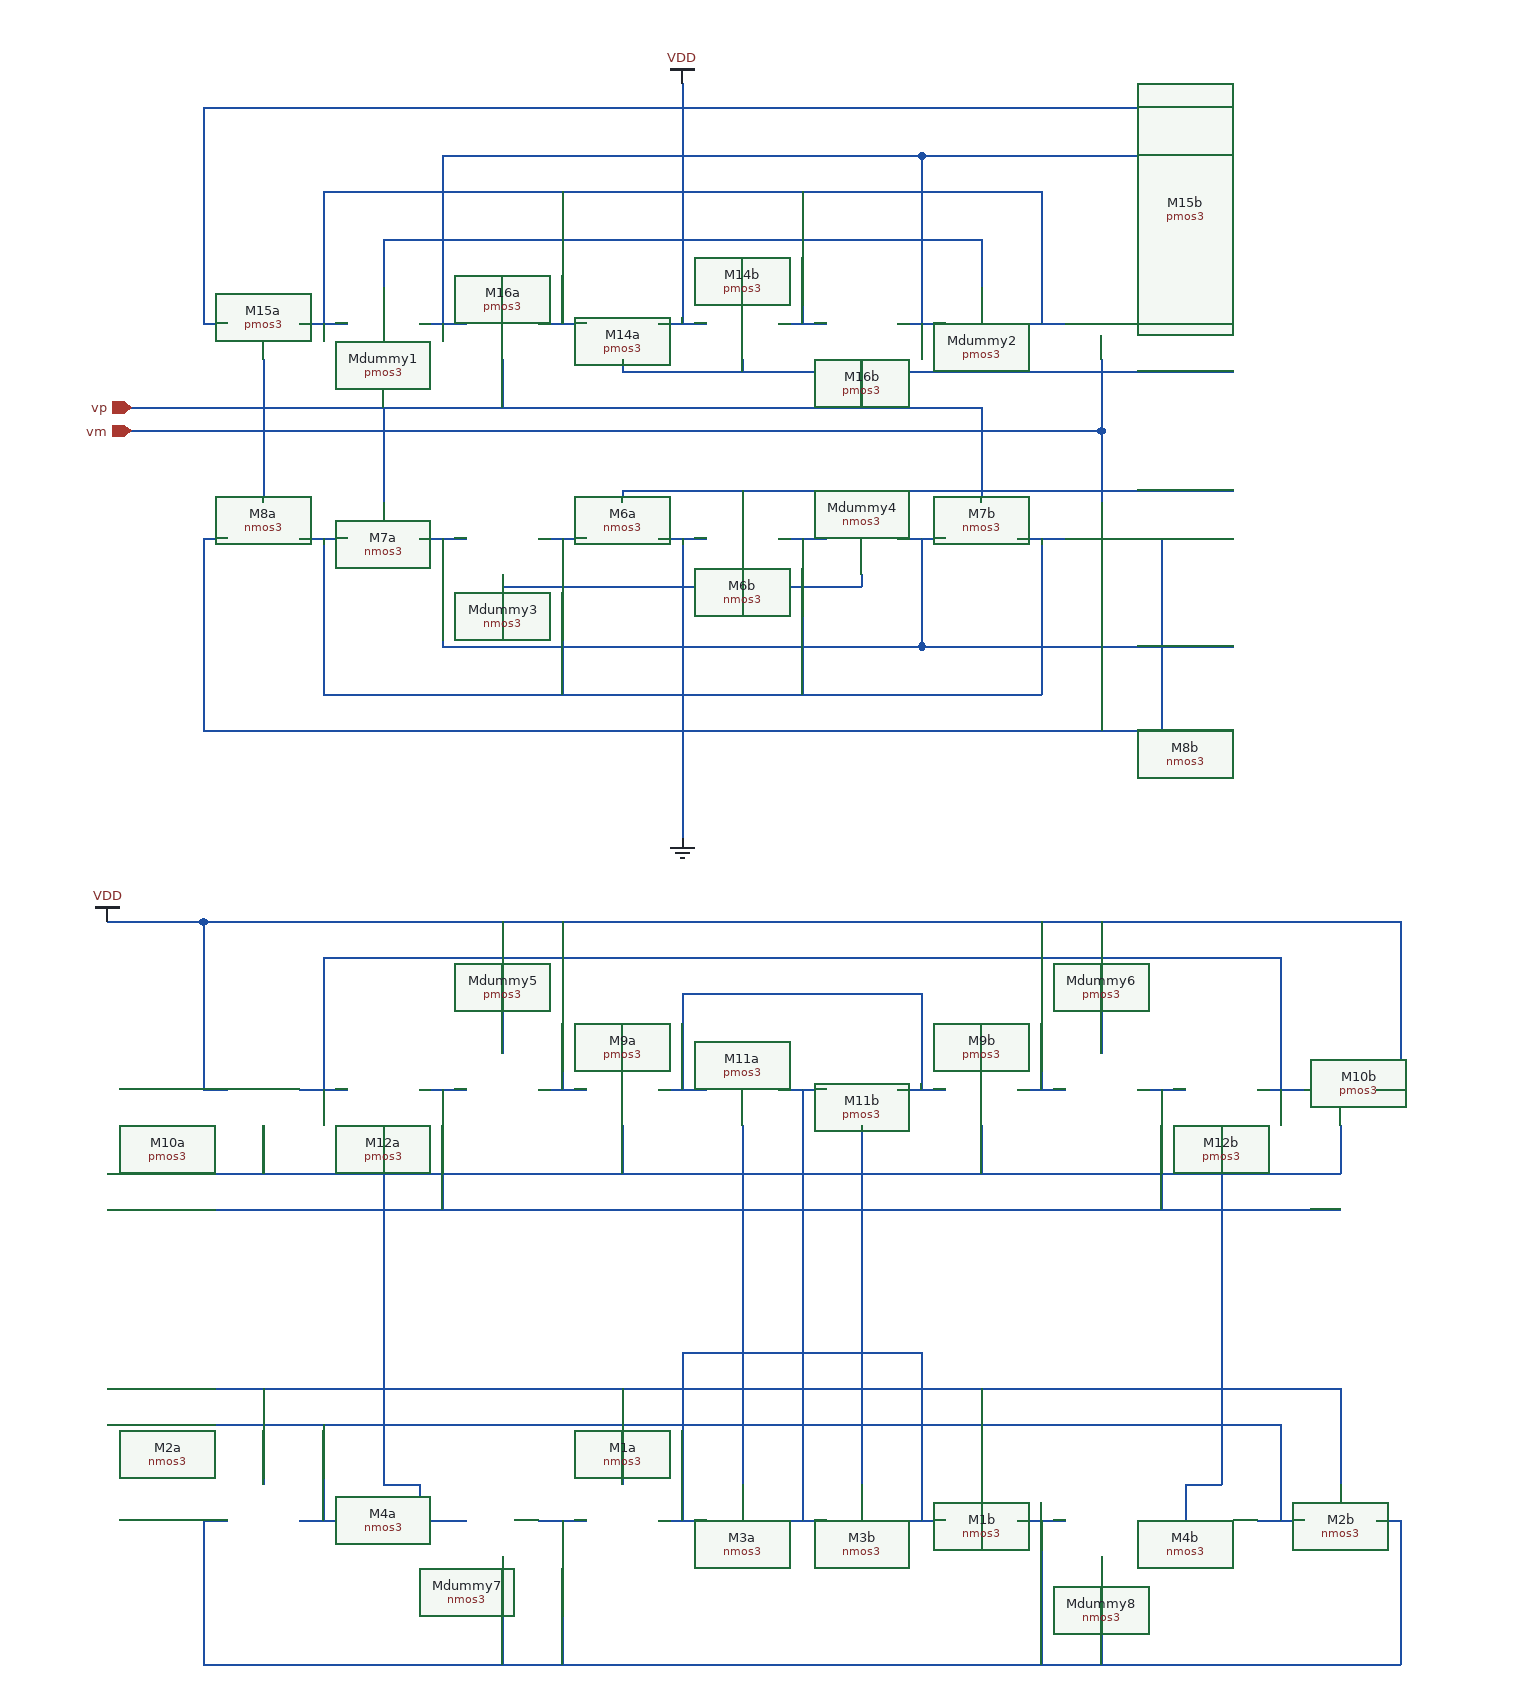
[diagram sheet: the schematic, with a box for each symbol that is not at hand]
v {xschem version=2.9.9 file_version=1.2 }
G {}
K {}
V {}
S {}
E {}
N 1240 -140 1280 -140 { lab=VDD}
N 1260 -340 1260 -140 { lab=VDD}
N 1240 40 1280 40 { lab=GND}
N 1260 40 1260 290 { lab=GND}
N 1140 40 1180 40 { lab=#net1}
N 1340 40 1380 40 { lab=#net1}
N 1210 -0 1210 10 { lab=#net2}
N 1310 -0 1310 10 { lab=#net2}
N 1210 -0 1720 -0 { lab=#net2}
N 1040 40 1080 40 { lab=#net3}
N 1440 40 1480 40 { lab=#net3}
N 940 40 980 40 { lab=#net1}
N 1540 40 1580 40 { lab=#net1}
N 1140 -140 1180 -140 { lab=#net4}
N 1340 -140 1380 -140 { lab=#net4}
N 1040 -140 1080 -140 { lab=#net5}
N 1440 -140 1480 -140 { lab=#net5}
N 940 -140 980 -140 { lab=#net4}
N 1540 -140 1580 -140 { lab=#net4}
N 1210 -110 1210 -100 { lab=#net6}
N 1210 -100 1720 -100 { lab=#net6}
N 1310 -110 1310 -100 { lab=#net6}
N 1110 80 1260 80 { lab=GND}
N 1260 80 1410 80 { lab=GND}
N 860 40 860 200 { lab=#net7}
N 1660 40 1660 200 { lab=#net7}
N 860 200 1720 200 { lab=#net7}
N 1640 40 1660 40 { lab=#net7}
N 860 40 880 40 { lab=#net7}
N 960 40 960 170 { lab=#net1}
N 960 170 1560 170 { lab=#net1}
N 1560 40 1560 170 { lab=#net1}
N 1160 40 1160 170 { lab=#net1}
N 1360 40 1360 170 { lab=#net1}
N 1110 70 1110 80 { lab=GND}
N 1410 70 1410 80 { lab=GND}
N 1060 40 1060 130 { lab=#net3}
N 1060 130 1460 130 { lab=#net3}
N 1460 40 1460 130 { lab=#net3}
N 1460 130 1720 130 { lab=#net3}
N 1010 -210 1260 -210 { lab=VDD}
N 1260 -210 1510 -210 { lab=VDD}
N 1510 -210 1510 -170 { lab=VDD}
N 1010 -210 1010 -170 { lab=VDD}
N 860 -140 880 -140 { lab=#net8}
N 1640 -140 1660 -140 { lab=#net8}
N 960 -250 960 -140 { lab=#net4}
N 960 -250 1560 -250 { lab=#net4}
N 1560 -250 1560 -140 { lab=#net4}
N 1160 -250 1160 -140 { lab=#net4}
N 1360 -250 1360 -140 { lab=#net4}
N 1060 -280 1060 -140 { lab=#net5}
N 1060 -280 1460 -280 { lab=#net5}
N 1460 -280 1460 -140 { lab=#net5}
N 1460 -280 1720 -280 { lab=#net5}
N 860 -320 860 -140 { lab=#net8}
N 860 -320 1660 -320 { lab=#net8}
N 1660 -320 1660 -140 { lab=#net8}
N 1660 -320 1720 -320 { lab=#net8}
N 800 -50 1610 -50 { lab=vm}
N 1610 -50 1610 10 { lab=vm}
N 1610 -110 1610 -50 { lab=vm}
N 910 -110 910 -50 { lab=vm}
N 910 -50 910 10 { lab=vm}
N 800 -70 1510 -70 { lab=vp}
N 1510 -70 1510 10 { lab=vp}
N 1410 -110 1410 -70 { lab=vp}
N 1010 -70 1010 10 { lab=vp}
N 1110 -110 1110 -70 { lab=vp}
N 860 500 880 500 { lab=VDD}
N 860 360 860 500 { lab=VDD}
N 1840 500 1860 500 { lab=VDD}
N 1860 360 1860 500 { lab=VDD}
N 1110 360 1110 470 { lab=VDD}
N 940 500 980 500 { lab=#net9}
N 1040 500 1080 500 { lab=#net10}
N 1140 500 1180 500 { lab=VDD}
N 860 360 1860 360 { lab=VDD}
N 1610 360 1610 470 { lab=VDD}
N 1740 500 1780 500 { lab=#net9}
N 1640 500 1680 500 { lab=#net10}
N 1540 500 1580 500 { lab=VDD}
N 1440 500 1480 500 { lab=#net11}
N 1340 500 1380 500 { lab=#net12}
N 1240 500 1280 500 { lab=#net11}
N 1160 360 1160 500 { lab=VDD}
N 1560 360 1560 500 { lab=VDD}
N 780 600 1810 600 { lab=#net10}
N 1010 530 1010 600 { lab=#net10}
N 1710 530 1710 600 { lab=#net10}
N 1310 530 1310 600 { lab=#net10}
N 1410 530 1410 600 { lab=#net10}
N 1360 500 1360 700 { lab=#net12}
N 910 530 910 570 { lab=#net13}
N 1810 530 1810 570 { lab=#net13}
N 780 570 1810 570 { lab=#net13}
N 1210 530 1210 570 { lab=#net13}
N 1510 530 1510 570 { lab=#net13}
N 1260 420 1260 500 { lab=#net11}
N 1260 420 1460 420 { lab=#net11}
N 1460 420 1460 500 { lab=#net11}
N 960 390 960 500 { lab=#net9}
N 960 390 1760 390 { lab=#net9}
N 1760 390 1760 500 { lab=#net9}
N 1060 500 1060 600 { lab=#net10}
N 1660 500 1660 600 { lab=#net10}
N 780 360 860 360 { lab=VDD}
N 940 860 980 860 { lab=#net14}
N 1040 860 1080 860 { lab=#net10}
N 1140 860 1180 860 { lab=#net15}
N 1240 860 1280 860 { lab=#net16}
N 1340 860 1380 860 { lab=#net12}
N 1440 860 1480 860 { lab=#net16}
N 1540 860 1580 860 { lab=#net15}
N 1640 860 1680 860 { lab=#net10}
N 940 860 980 860 { lab=#net14}
N 1040 860 1080 860 { lab=#net10}
N 1740 860 1780 860 { lab=#net14}
N 860 860 880 860 { lab=#net15}
N 1840 860 1860 860 { lab=#net15}
N 860 860 860 980 { lab=#net15}
N 860 980 1860 980 { lab=#net15}
N 1860 860 1860 980 { lab=#net15}
N 1110 890 1110 980 { lab=#net15}
N 1610 890 1610 980 { lab=#net15}
N 1360 700 1360 860 { lab=#net12}
N 1160 860 1160 980 { lab=#net15}
N 1560 860 1560 980 { lab=#net15}
N 960 780 960 860 { lab=#net14}
N 1760 780 1760 860 { lab=#net14}
N 780 780 1760 780 { lab=#net14}
N 1010 600 1010 830 { lab=#net10}
N 1710 600 1710 830 { lab=#net10}
N 1040 830 1040 860 { lab=#net10}
N 1010 830 1040 830 { lab=#net10}
N 1680 830 1680 860 { lab=#net10}
N 1680 830 1710 830 { lab=#net10}
N 910 750 910 830 { lab=#net17}
N 1210 750 1210 830 { lab=#net17}
N 1510 750 1510 830 { lab=#net17}
N 1810 750 1810 830 { lab=#net17}
N 780 750 1810 750 { lab=#net17}
N 1310 600 1310 830 { lab=#net10}
N 1410 600 1410 830 { lab=#net10}
N 1260 720 1260 860 { lab=#net16}
N 1460 720 1460 860 { lab=#net16}
N 1260 720 1460 720 { lab=#net16}
C {madvlsi/pmos3.sym} 1010 -140 1 0 {name=Mdummy1
L=0.6
W=1.5
body=VDD
nf=1
mult=1
ad="'int((nf+1)/2) * W/nf * 0.29'" 
pd="'2*int((nf+1)/2) * (W/nf + 0.29)'"
as="'int((nf+2)/2) * W/nf * 0.29'" 
ps="'2*int((nf+2)/2) * (W/nf + 0.29)'"
nrd="'0.29 / W'" nrs="'0.29 / W'"
sa=0 sb=0 sd=0
model=pfet_01v8
spiceprefix=X
}
C {madvlsi/pmos3.sym} 1110 -140 3 0 {name=M16a
L=0.6
W=1.5
body=VDD
nf=1
mult=1
ad="'int((nf+1)/2) * W/nf * 0.29'" 
pd="'2*int((nf+1)/2) * (W/nf + 0.29)'"
as="'int((nf+2)/2) * W/nf * 0.29'" 
ps="'2*int((nf+2)/2) * (W/nf + 0.29)'"
nrd="'0.29 / W'" nrs="'0.29 / W'"
sa=0 sb=0 sd=0
model=pfet_01v8
spiceprefix=X
}
C {madvlsi/pmos3.sym} 1210 -140 3 0 {name=M14a
L=0.6
W=1.5
body=VDD
nf=1
mult=1
ad="'int((nf+1)/2) * W/nf * 0.29'" 
pd="'2*int((nf+1)/2) * (W/nf + 0.29)'"
as="'int((nf+2)/2) * W/nf * 0.29'" 
ps="'2*int((nf+2)/2) * (W/nf + 0.29)'"
nrd="'0.29 / W'" nrs="'0.29 / W'"
sa=0 sb=0 sd=0
model=pfet_01v8
spiceprefix=X
}
C {madvlsi/pmos3.sym} 1310 -140 3 0 {name=M14b
L=0.6
W=1.5
body=VDD
nf=1
mult=1
ad="'int((nf+1)/2) * W/nf * 0.29'" 
pd="'2*int((nf+1)/2) * (W/nf + 0.29)'"
as="'int((nf+2)/2) * W/nf * 0.29'" 
ps="'2*int((nf+2)/2) * (W/nf + 0.29)'"
nrd="'0.29 / W'" nrs="'0.29 / W'"
sa=0 sb=0 sd=0
model=pfet_01v8
spiceprefix=X
}
C {madvlsi/pmos3.sym} 910 -140 3 0 {name=M15a
L=0.6
W=1.5
body=VDD
nf=1
mult=1
ad="'int((nf+1)/2) * W/nf * 0.29'" 
pd="'2*int((nf+1)/2) * (W/nf + 0.29)'"
as="'int((nf+2)/2) * W/nf * 0.29'" 
ps="'2*int((nf+2)/2) * (W/nf + 0.29)'"
nrd="'0.29 / W'" nrs="'0.29 / W'"
sa=0 sb=0 sd=0
model=pfet_01v8
spiceprefix=X
}
C {madvlsi/pmos3.sym} 1410 -140 3 0 {name=M16b
L=0.6
W=1.5
body=VDD
nf=1
mult=1
ad="'int((nf+1)/2) * W/nf * 0.29'" 
pd="'2*int((nf+1)/2) * (W/nf + 0.29)'"
as="'int((nf+2)/2) * W/nf * 0.29'" 
ps="'2*int((nf+2)/2) * (W/nf + 0.29)'"
nrd="'0.29 / W'" nrs="'0.29 / W'"
sa=0 sb=0 sd=0
model=pfet_01v8
spiceprefix=X
}
C {madvlsi/nmos3.sym} 1110 40 1 1 {name=Mdummy3
L=0.6
W=1.5
body=GND
nf=1
mult=1
ad="'int((nf+1)/2) * W/nf * 0.29'" 
pd="'2*int((nf+1)/2) * (W/nf + 0.29)'"
as="'int((nf+2)/2) * W/nf * 0.29'" 
ps="'2*int((nf+2)/2) * (W/nf + 0.29)'"
nrd="'0.29 / W'" nrs="'0.29 / W'"
sa=0 sb=0 sd=0
model=nfet_01v8
spiceprefix=X
}
C {madvlsi/nmos3.sym} 1210 40 3 1 {name=M6a
L=0.6
W=1.5
body=GND
nf=1
mult=1
ad="'int((nf+1)/2) * W/nf * 0.29'" 
pd="'2*int((nf+1)/2) * (W/nf + 0.29)'"
as="'int((nf+2)/2) * W/nf * 0.29'" 
ps="'2*int((nf+2)/2) * (W/nf + 0.29)'"
nrd="'0.29 / W'" nrs="'0.29 / W'"
sa=0 sb=0 sd=0
model=nfet_01v8
spiceprefix=X
}
C {madvlsi/nmos3.sym} 1310 40 3 1 {name=M6b
L=0.6
W=1.5
body=GND
nf=1
mult=1
ad="'int((nf+1)/2) * W/nf * 0.29'" 
pd="'2*int((nf+1)/2) * (W/nf + 0.29)'"
as="'int((nf+2)/2) * W/nf * 0.29'" 
ps="'2*int((nf+2)/2) * (W/nf + 0.29)'"
nrd="'0.29 / W'" nrs="'0.29 / W'"
sa=0 sb=0 sd=0
model=nfet_01v8
spiceprefix=X
}
C {madvlsi/nmos3.sym} 1410 40 1 1 {name=Mdummy4
L=0.6
W=1.5
body=GND
nf=1
mult=1
ad="'int((nf+1)/2) * W/nf * 0.29'" 
pd="'2*int((nf+1)/2) * (W/nf + 0.29)'"
as="'int((nf+2)/2) * W/nf * 0.29'" 
ps="'2*int((nf+2)/2) * (W/nf + 0.29)'"
nrd="'0.29 / W'" nrs="'0.29 / W'"
sa=0 sb=0 sd=0
model=nfet_01v8
spiceprefix=X
}
C {madvlsi/nmos3.sym} 910 40 3 1 {name=M8a
L=0.6
W=1.5
body=GND
nf=1
mult=1
ad="'int((nf+1)/2) * W/nf * 0.29'" 
pd="'2*int((nf+1)/2) * (W/nf + 0.29)'"
as="'int((nf+2)/2) * W/nf * 0.29'" 
ps="'2*int((nf+2)/2) * (W/nf + 0.29)'"
nrd="'0.29 / W'" nrs="'0.29 / W'"
sa=0 sb=0 sd=0
model=nfet_01v8
spiceprefix=X
}
C {madvlsi/nmos3.sym} 1010 40 3 1 {name=M7a
L=0.6
W=1.5
body=GND
nf=1
mult=1
ad="'int((nf+1)/2) * W/nf * 0.29'" 
pd="'2*int((nf+1)/2) * (W/nf + 0.29)'"
as="'int((nf+2)/2) * W/nf * 0.29'" 
ps="'2*int((nf+2)/2) * (W/nf + 0.29)'"
nrd="'0.29 / W'" nrs="'0.29 / W'"
sa=0 sb=0 sd=0
model=nfet_01v8
spiceprefix=X
}
C {madvlsi/pmos3.sym} 1510 -140 1 0 {name=Mdummy2
L=0.6
W=1.5
body=VDD
nf=1
mult=1
ad="'int((nf+1)/2) * W/nf * 0.29'" 
pd="'2*int((nf+1)/2) * (W/nf + 0.29)'"
as="'int((nf+2)/2) * W/nf * 0.29'" 
ps="'2*int((nf+2)/2) * (W/nf + 0.29)'"
nrd="'0.29 / W'" nrs="'0.29 / W'"
sa=0 sb=0 sd=0
model=pfet_01v8
spiceprefix=X
}
C {madvlsi/pmos3.sym} 1610 -140 3 0 {name=M15b
L=0.6
W=1.5
body=VDD
nf=1
mult=1
ad="'int((nf+1)/2) * W/nf * 0.29'" 
pd="'2*int((nf+1)/2) * (W/nf + 0.29)'"
as="'int((nf+2)/2) * W/nf * 0.29'" 
ps="'2*int((nf+2)/2) * (W/nf + 0.29)'"
nrd="'0.29 / W'" nrs="'0.29 / W'"
sa=0 sb=0 sd=0
model=pfet_01v8
spiceprefix=X
}
C {madvlsi/nmos3.sym} 1510 40 3 1 {name=M7b
L=0.6
W=1.5
body=GND
nf=1
mult=1
ad="'int((nf+1)/2) * W/nf * 0.29'" 
pd="'2*int((nf+1)/2) * (W/nf + 0.29)'"
as="'int((nf+2)/2) * W/nf * 0.29'" 
ps="'2*int((nf+2)/2) * (W/nf + 0.29)'"
nrd="'0.29 / W'" nrs="'0.29 / W'"
sa=0 sb=0 sd=0
model=nfet_01v8
spiceprefix=X
}
C {madvlsi/nmos3.sym} 1610 40 3 1 {name=M8b
L=0.6
W=1.5
body=GND
nf=1
mult=1
ad="'int((nf+1)/2) * W/nf * 0.29'" 
pd="'2*int((nf+1)/2) * (W/nf + 0.29)'"
as="'int((nf+2)/2) * W/nf * 0.29'" 
ps="'2*int((nf+2)/2) * (W/nf + 0.29)'"
nrd="'0.29 / W'" nrs="'0.29 / W'"
sa=0 sb=0 sd=0
model=nfet_01v8
spiceprefix=X
}
C {devices/ipin.sym} 800 -50 0 0 {name=p9 lab=vm}
C {devices/ipin.sym} 800 -70 0 0 {name=p10 lab=vp}
C {madvlsi/vdd.sym} 1260 -340 0 0 {name=l1 lab=VDD}
C {madvlsi/gnd.sym} 1260 290 0 0 {name=l2 lab=GND}
C {madvlsi/pmos3.sym} 910 500 3 0 {name=M10a
L=0.6
W=1.5
body=VDD
nf=1
mult=1
ad="'int((nf+1)/2) * W/nf * 0.29'" 
pd="'2*int((nf+1)/2) * (W/nf + 0.29)'"
as="'int((nf+2)/2) * W/nf * 0.29'" 
ps="'2*int((nf+2)/2) * (W/nf + 0.29)'"
nrd="'0.29 / W'" nrs="'0.29 / W'"
sa=0 sb=0 sd=0
model=pfet_01v8
spiceprefix=X
}
C {madvlsi/pmos3.sym} 1210 500 3 0 {name=M9a
L=0.6
W=1.5
body=VDD
nf=1
mult=1
ad="'int((nf+1)/2) * W/nf * 0.29'" 
pd="'2*int((nf+1)/2) * (W/nf + 0.29)'"
as="'int((nf+2)/2) * W/nf * 0.29'" 
ps="'2*int((nf+2)/2) * (W/nf + 0.29)'"
nrd="'0.29 / W'" nrs="'0.29 / W'"
sa=0 sb=0 sd=0
model=pfet_01v8
spiceprefix=X
}
C {madvlsi/pmos3.sym} 1010 500 3 0 {name=M12a
L=0.6
W=1.5
body=VDD
nf=1
mult=1
ad="'int((nf+1)/2) * W/nf * 0.29'" 
pd="'2*int((nf+1)/2) * (W/nf + 0.29)'"
as="'int((nf+2)/2) * W/nf * 0.29'" 
ps="'2*int((nf+2)/2) * (W/nf + 0.29)'"
nrd="'0.29 / W'" nrs="'0.29 / W'"
sa=0 sb=0 sd=0
model=pfet_01v8
spiceprefix=X
}
C {madvlsi/pmos3.sym} 1310 500 3 0 {name=M11a
L=0.6
W=1.5
body=VDD
nf=1
mult=1
ad="'int((nf+1)/2) * W/nf * 0.29'" 
pd="'2*int((nf+1)/2) * (W/nf + 0.29)'"
as="'int((nf+2)/2) * W/nf * 0.29'" 
ps="'2*int((nf+2)/2) * (W/nf + 0.29)'"
nrd="'0.29 / W'" nrs="'0.29 / W'"
sa=0 sb=0 sd=0
model=pfet_01v8
spiceprefix=X
}
C {madvlsi/pmos3.sym} 1410 500 3 0 {name=M11b
L=0.6
W=1.5
body=VDD
nf=1
mult=1
ad="'int((nf+1)/2) * W/nf * 0.29'" 
pd="'2*int((nf+1)/2) * (W/nf + 0.29)'"
as="'int((nf+2)/2) * W/nf * 0.29'" 
ps="'2*int((nf+2)/2) * (W/nf + 0.29)'"
nrd="'0.29 / W'" nrs="'0.29 / W'"
sa=0 sb=0 sd=0
model=pfet_01v8
spiceprefix=X
}
C {madvlsi/pmos3.sym} 1710 500 3 0 {name=M12b
L=0.6
W=1.5
body=VDD
nf=1
mult=1
ad="'int((nf+1)/2) * W/nf * 0.29'" 
pd="'2*int((nf+1)/2) * (W/nf + 0.29)'"
as="'int((nf+2)/2) * W/nf * 0.29'" 
ps="'2*int((nf+2)/2) * (W/nf + 0.29)'"
nrd="'0.29 / W'" nrs="'0.29 / W'"
sa=0 sb=0 sd=0
model=pfet_01v8
spiceprefix=X
}
C {madvlsi/pmos3.sym} 1510 500 3 0 {name=M9b
L=0.6
W=1.5
body=VDD
nf=1
mult=1
ad="'int((nf+1)/2) * W/nf * 0.29'" 
pd="'2*int((nf+1)/2) * (W/nf + 0.29)'"
as="'int((nf+2)/2) * W/nf * 0.29'" 
ps="'2*int((nf+2)/2) * (W/nf + 0.29)'"
nrd="'0.29 / W'" nrs="'0.29 / W'"
sa=0 sb=0 sd=0
model=pfet_01v8
spiceprefix=X
}
C {madvlsi/pmos3.sym} 1810 500 3 0 {name=M10b
L=0.6
W=1.5
body=VDD
nf=1
mult=1
ad="'int((nf+1)/2) * W/nf * 0.29'" 
pd="'2*int((nf+1)/2) * (W/nf + 0.29)'"
as="'int((nf+2)/2) * W/nf * 0.29'" 
ps="'2*int((nf+2)/2) * (W/nf + 0.29)'"
nrd="'0.29 / W'" nrs="'0.29 / W'"
sa=0 sb=0 sd=0
model=pfet_01v8
spiceprefix=X
}
C {madvlsi/pmos3.sym} 1110 500 1 0 {name=Mdummy5
L=0.6
W=1.5
body=VDD
nf=1
mult=1
ad="'int((nf+1)/2) * W/nf * 0.29'" 
pd="'2*int((nf+1)/2) * (W/nf + 0.29)'"
as="'int((nf+2)/2) * W/nf * 0.29'" 
ps="'2*int((nf+2)/2) * (W/nf + 0.29)'"
nrd="'0.29 / W'" nrs="'0.29 / W'"
sa=0 sb=0 sd=0
model=pfet_01v8
spiceprefix=X
}
C {madvlsi/pmos3.sym} 1610 500 1 0 {name=Mdummy6
L=0.6
W=1.5
body=VDD
nf=1
mult=1
ad="'int((nf+1)/2) * W/nf * 0.29'" 
pd="'2*int((nf+1)/2) * (W/nf + 0.29)'"
as="'int((nf+2)/2) * W/nf * 0.29'" 
ps="'2*int((nf+2)/2) * (W/nf + 0.29)'"
nrd="'0.29 / W'" nrs="'0.29 / W'"
sa=0 sb=0 sd=0
model=pfet_01v8
spiceprefix=X
}
C {madvlsi/vdd.sym} 780 360 3 0 {name=l3 lab=VDD}
C {madvlsi/nmos3.sym} 910 860 3 1 {name=M2a
L=0.6
W=1.5
body=GND
nf=1
mult=1
ad="'int((nf+1)/2) * W/nf * 0.29'" 
pd="'2*int((nf+1)/2) * (W/nf + 0.29)'"
as="'int((nf+2)/2) * W/nf * 0.29'" 
ps="'2*int((nf+2)/2) * (W/nf + 0.29)'"
nrd="'0.29 / W'" nrs="'0.29 / W'"
sa=0 sb=0 sd=0
model=nfet_01v8
spiceprefix=X
}
C {madvlsi/nmos3.sym} 1010 860 3 1 {name=M4a
L=0.6
W=1.5
body=GND
nf=1
mult=1
ad="'int((nf+1)/2) * W/nf * 0.29'" 
pd="'2*int((nf+1)/2) * (W/nf + 0.29)'"
as="'int((nf+2)/2) * W/nf * 0.29'" 
ps="'2*int((nf+2)/2) * (W/nf + 0.29)'"
nrd="'0.29 / W'" nrs="'0.29 / W'"
sa=0 sb=0 sd=0
model=nfet_01v8
spiceprefix=X
}
C {madvlsi/nmos3.sym} 1110 860 1 1 {name=Mdummy7
L=0.6
W=1.5
body=GND
nf=1
mult=1
ad="'int((nf+1)/2) * W/nf * 0.29'" 
pd="'2*int((nf+1)/2) * (W/nf + 0.29)'"
as="'int((nf+2)/2) * W/nf * 0.29'" 
ps="'2*int((nf+2)/2) * (W/nf + 0.29)'"
nrd="'0.29 / W'" nrs="'0.29 / W'"
sa=0 sb=0 sd=0
model=nfet_01v8
spiceprefix=X
}
C {madvlsi/nmos3.sym} 1210 860 3 1 {name=M1a
L=0.6
W=1.5
body=GND
nf=1
mult=1
ad="'int((nf+1)/2) * W/nf * 0.29'" 
pd="'2*int((nf+1)/2) * (W/nf + 0.29)'"
as="'int((nf+2)/2) * W/nf * 0.29'" 
ps="'2*int((nf+2)/2) * (W/nf + 0.29)'"
nrd="'0.29 / W'" nrs="'0.29 / W'"
sa=0 sb=0 sd=0
model=nfet_01v8
spiceprefix=X
}
C {madvlsi/nmos3.sym} 1310 860 3 1 {name=M3a
L=0.6
W=1.5
body=GND
nf=1
mult=1
ad="'int((nf+1)/2) * W/nf * 0.29'" 
pd="'2*int((nf+1)/2) * (W/nf + 0.29)'"
as="'int((nf+2)/2) * W/nf * 0.29'" 
ps="'2*int((nf+2)/2) * (W/nf + 0.29)'"
nrd="'0.29 / W'" nrs="'0.29 / W'"
sa=0 sb=0 sd=0
model=nfet_01v8
spiceprefix=X
}
C {madvlsi/nmos3.sym} 1410 860 3 1 {name=M3b
L=0.6
W=1.5
body=GND
nf=1
mult=1
ad="'int((nf+1)/2) * W/nf * 0.29'" 
pd="'2*int((nf+1)/2) * (W/nf + 0.29)'"
as="'int((nf+2)/2) * W/nf * 0.29'" 
ps="'2*int((nf+2)/2) * (W/nf + 0.29)'"
nrd="'0.29 / W'" nrs="'0.29 / W'"
sa=0 sb=0 sd=0
model=nfet_01v8
spiceprefix=X
}
C {madvlsi/nmos3.sym} 1510 860 3 1 {name=M1b
L=0.6
W=1.5
body=GND
nf=1
mult=1
ad="'int((nf+1)/2) * W/nf * 0.29'" 
pd="'2*int((nf+1)/2) * (W/nf + 0.29)'"
as="'int((nf+2)/2) * W/nf * 0.29'" 
ps="'2*int((nf+2)/2) * (W/nf + 0.29)'"
nrd="'0.29 / W'" nrs="'0.29 / W'"
sa=0 sb=0 sd=0
model=nfet_01v8
spiceprefix=X
}
C {madvlsi/nmos3.sym} 1610 860 1 1 {name=Mdummy8
L=0.6
W=1.5
body=GND
nf=1
mult=1
ad="'int((nf+1)/2) * W/nf * 0.29'" 
pd="'2*int((nf+1)/2) * (W/nf + 0.29)'"
as="'int((nf+2)/2) * W/nf * 0.29'" 
ps="'2*int((nf+2)/2) * (W/nf + 0.29)'"
nrd="'0.29 / W'" nrs="'0.29 / W'"
sa=0 sb=0 sd=0
model=nfet_01v8
spiceprefix=X
}
C {madvlsi/nmos3.sym} 1710 860 3 1 {name=M4b
L=0.6
W=1.5
body=GND
nf=1
mult=1
ad="'int((nf+1)/2) * W/nf * 0.29'" 
pd="'2*int((nf+1)/2) * (W/nf + 0.29)'"
as="'int((nf+2)/2) * W/nf * 0.29'" 
ps="'2*int((nf+2)/2) * (W/nf + 0.29)'"
nrd="'0.29 / W'" nrs="'0.29 / W'"
sa=0 sb=0 sd=0
model=nfet_01v8
spiceprefix=X
}
C {madvlsi/nmos3.sym} 1810 860 3 1 {name=M2b
L=0.6
W=1.5
body=GND
nf=1
mult=1
ad="'int((nf+1)/2) * W/nf * 0.29'" 
pd="'2*int((nf+1)/2) * (W/nf + 0.29)'"
as="'int((nf+2)/2) * W/nf * 0.29'" 
ps="'2*int((nf+2)/2) * (W/nf + 0.29)'"
nrd="'0.29 / W'" nrs="'0.29 / W'"
sa=0 sb=0 sd=0
model=nfet_01v8
spiceprefix=X
}
